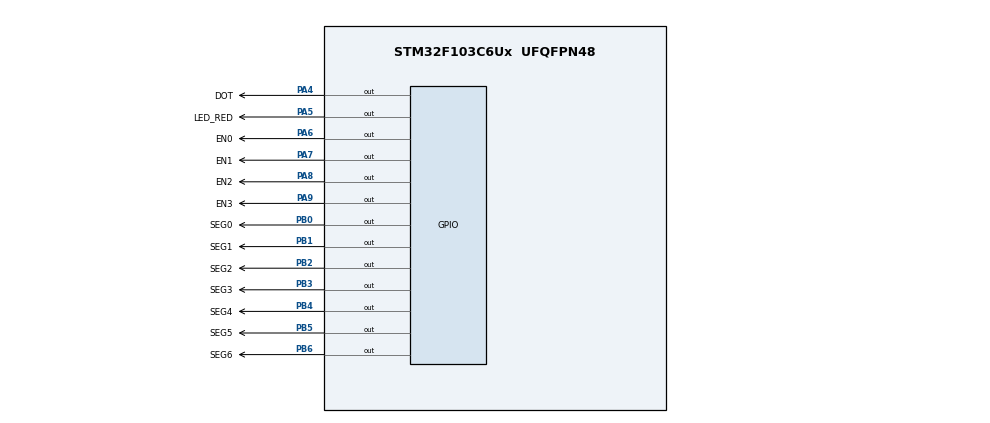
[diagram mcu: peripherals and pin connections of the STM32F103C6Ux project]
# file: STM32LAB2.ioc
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Mcu.Family=STM32F1
Mcu.Name=STM32F103C6Ux
Mcu.Package=UFQFPN48
NVIC.PriorityGroup=NVIC_PRIORITYGROUP_4
NVIC.TIM2_IRQn=true\:0\:0\:false\:false\:true\:true\:true
PA4.GPIO_Label=DOT
PA4.Signal=GPIO_Output
PA5.GPIO_Label=LED_RED
PA5.Signal=GPIO_Output
PA6.GPIO_Label=EN0
PA6.Signal=GPIO_Output
PA7.GPIO_Label=EN1
PA7.Signal=GPIO_Output
PA8.GPIO_Label=EN2
PA8.Signal=GPIO_Output
PA9.GPIO_Label=EN3
PA9.Signal=GPIO_Output
PB0.GPIO_Label=SEG0
PB0.Signal=GPIO_Output
PB1.GPIO_Label=SEG1
PB1.Signal=GPIO_Output
PB2.GPIO_Label=SEG2
PB2.Signal=GPIO_Output
PB3.GPIO_Label=SEG3
PB3.Signal=GPIO_Output
PB4.GPIO_Label=SEG4
PB4.Signal=GPIO_Output
PB5.GPIO_Label=SEG5
PB5.Signal=GPIO_Output
PB6.GPIO_Label=SEG6
PB6.Signal=GPIO_Output
ProjectManager.HeapSize=0x200
ProjectManager.StackSize=0x400
ProjectManager.TargetToolchain=STM32CubeIDE
RCC.APB1Freq_Value=8000000
RCC.APB2Freq_Value=8000000
TIM2.Period=9
TIM2.Prescaler=7999
VP_SYS_VS_ND.Mode=No_Debug
VP_TIM2_VS_ClockSourceINT.Mode=Internal
board=custom

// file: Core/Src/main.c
/* USER CODE BEGIN Header */
/**
  ******************************************************************************
  * @file           : main.c
  * @brief          : Main program body
  ******************************************************************************
  * @attention
  *
  * <h2><center>&copy; Copyright (c) 2024 STMicroelectronics.
  * All rights reserved.</center></h2>
  *
  * This software component is licensed by ST under BSD 3-Clause license,
  * the "License"; You may not use this file except in compliance with the
  * License. You may obtain a copy of the License at:
  *                        opensource.org/licenses/BSD-3-Clause
  *
  ******************************************************************************
  */
/* USER CODE END Header */
#include "main.h"

/* USER CODE BEGIN Includes */
#include "timer.h"
/* USER CODE END Includes */

TIM_HandleTypeDef htim2;

void SystemClock_Config(void);
static void MX_GPIO_Init(void);
static void MX_TIM2_Init(void);

/* USER CODE BEGIN 0 */
const int MAX_LED_MATRIX = 8;
int index_led_matrix = 0;
int index_led_matrix_shift = 0;
uint8_t matrix_buffer[8] = {0x00, 0xfc, 0xfe, 0x11, 0x11, 0xfe, 0xfc, 0x00}; // Display "A"

void displayLEDMatrix(int index)
{
	HAL_GPIO_WritePin(ROW0_GPIO_Port, ROW0_Pin, ((matrix_buffer[index] >> 0) & 1) ? GPIO_PIN_RESET : GPIO_PIN_SET);
	HAL_GPIO_WritePin(ROW1_GPIO_Port, ROW1_Pin, ((matrix_buffer[index] >> 1) & 1) ? GPIO_PIN_RESET : GPIO_PIN_SET);
	HAL_GPIO_WritePin(ROW2_GPIO_Port, ROW2_Pin, ((matrix_buffer[index] >> 2) & 1) ? GPIO_PIN_RESET : GPIO_PIN_SET);
	HAL_GPIO_WritePin(ROW3_GPIO_Port, ROW3_Pin, ((matrix_buffer[index] >> 3) & 1) ? GPIO_PIN_RESET : GPIO_PIN_SET);
	HAL_GPIO_WritePin(ROW4_GPIO_Port, ROW4_Pin, ((matrix_buffer[index] >> 4) & 1) ? GPIO_PIN_RESET : GPIO_PIN_SET);
	HAL_GPIO_WritePin(ROW5_GPIO_Port, ROW5_Pin, ((matrix_buffer[index] >> 5) & 1) ? GPIO_PIN_RESET : GPIO_PIN_SET);
	HAL_GPIO_WritePin(ROW6_GPIO_Port, ROW6_Pin, ((matrix_buffer[index] >> 6) & 1) ? GPIO_PIN_RESET : GPIO_PIN_SET);
	HAL_GPIO_WritePin(ROW7_GPIO_Port, ROW7_Pin, ((matrix_buffer[index] >> 7) & 1) ? GPIO_PIN_RESET : GPIO_PIN_SET);
}

void updateLEDMatrix(int index, int shift)
{
	int index_shift = (index + shift) % 8;

	switch(index)
	{
	case 0:
		HAL_GPIO_WritePin(ENM7_GPIO_Port, ENM7_Pin, 1);
		displayLEDMatrix(index_shift);
		HAL_GPIO_WritePin(ENM0_GPIO_Port, ENM0_Pin, 0);
		break;
	case 1:
		HAL_GPIO_WritePin(ENM0_GPIO_Port, ENM0_Pin, 1);
		displayLEDMatrix(index_shift);
		HAL_GPIO_WritePin(ENM1_GPIO_Port, ENM1_Pin, 0);
		break;
	case 2:
		HAL_GPIO_WritePin(ENM1_GPIO_Port, ENM1_Pin, 1);
		displayLEDMatrix(index_shift);
		HAL_GPIO_WritePin(ENM2_GPIO_Port, ENM2_Pin, 0);
		break;
	case 3:
		HAL_GPIO_WritePin(ENM2_GPIO_Port, ENM2_Pin, 1);
		displayLEDMatrix(index_shift);
		HAL_GPIO_WritePin(ENM3_GPIO_Port, ENM3_Pin, 0);
		break;
	case 4:
		HAL_GPIO_WritePin(ENM3_GPIO_Port, ENM3_Pin, 1);
		displayLEDMatrix(index_shift);
		HAL_GPIO_WritePin(ENM4_GPIO_Port, ENM4_Pin, 0);
		break;
	case 5:
		HAL_GPIO_WritePin(ENM4_GPIO_Port, ENM4_Pin, 1);
		displayLEDMatrix(index_shift);
		HAL_GPIO_WritePin(ENM5_GPIO_Port, ENM5_Pin, 0);
		break;
	case 6:
		HAL_GPIO_WritePin(ENM5_GPIO_Port, ENM5_Pin, 1);
		displayLEDMatrix(index_shift);
		HAL_GPIO_WritePin(ENM6_GPIO_Port, ENM6_Pin, 0);
		break;
	case 7:
		HAL_GPIO_WritePin(ENM6_GPIO_Port, ENM6_Pin, 1);
		displayLEDMatrix(index_shift);
		HAL_GPIO_WritePin(ENM7_GPIO_Port, ENM7_Pin, 0);
		break;
	default:
		break;
	}
}
/* USER CODE END 0 */

int main(void)
{

  /* MCU Configuration--------------------------------------------------------*/

  /* Reset of all peripherals, Initializes the Flash interface and the Systick. */
  HAL_Init();

  /* Configure the system clock */
  SystemClock_Config();

  /* Initialize all configured peripherals */
  MX_GPIO_Init();
  MX_TIM2_Init();
  /* USER CODE BEGIN 2 */
  HAL_TIM_Base_Start_IT(&htim2);
  /* USER CODE END 2 */

  /* Infinite loop */
  /* USER CODE BEGIN WHILE */
  HAL_GPIO_WritePin(GPIOA, EN0_Pin | EN1_Pin | EN2_Pin | EN3_Pin, 1);
  HAL_GPIO_WritePin(DOT_GPIO_Port, DOT_Pin, 1);
  HAL_GPIO_WritePin(GPIOA, ENM0_Pin | ENM1_Pin | ENM2_Pin | ENM3_Pin
		  | ENM4_Pin | ENM5_Pin | ENM6_Pin | ENM7_Pin, 1);

  set_timer(0, 250);
  while (1)
  {
	  if (timer_flag[0] == 1)
	  {
		  updateLEDMatrix(index_led_matrix, index_led_matrix_shift);
		  index_led_matrix++;
		  if (index_led_matrix >= MAX_LED_MATRIX)
		  {
			  index_led_matrix = 0;
			  index_led_matrix_shift++;
			  if (index_led_matrix_shift >= MAX_LED_MATRIX) index_led_matrix_shift = 0;
		  }
		  set_timer(0, 250);
	  }
    /* USER CODE END WHILE */

  }
}

void SystemClock_Config(void)
{
  RCC_OscInitTypeDef RCC_OscInitStruct = {0};
  RCC_ClkInitTypeDef RCC_ClkInitStruct = {0};

  /** Initializes the RCC Oscillators according to the specified parameters
  * in the RCC_OscInitTypeDef structure.
  */
  RCC_OscInitStruct.OscillatorType = RCC_OSCILLATORTYPE_HSI;
  RCC_OscInitStruct.HSIState = RCC_HSI_ON;
  RCC_OscInitStruct.HSICalibrationValue = RCC_HSICALIBRATION_DEFAULT;
  RCC_OscInitStruct.PLL.PLLState = RCC_PLL_NONE;
  if (HAL_RCC_OscConfig(&RCC_OscInitStruct) != HAL_OK)
  {
    Error_Handler();
  }
  /** Initializes the CPU, AHB and APB buses clocks
  */
  RCC_ClkInitStruct.ClockType = RCC_CLOCKTYPE_HCLK|RCC_CLOCKTYPE_SYSCLK
                              |RCC_CLOCKTYPE_PCLK1|RCC_CLOCKTYPE_PCLK2;
  RCC_ClkInitStruct.SYSCLKSource = RCC_SYSCLKSOURCE_HSI;
  RCC_ClkInitStruct.AHBCLKDivider = RCC_SYSCLK_DIV1;
  RCC_ClkInitStruct.APB1CLKDivider = RCC_HCLK_DIV1;
  RCC_ClkInitStruct.APB2CLKDivider = RCC_HCLK_DIV1;

  if (HAL_RCC_ClockConfig(&RCC_ClkInitStruct, FLASH_LATENCY_0) != HAL_OK)
  {
    Error_Handler();
  }
}

static void MX_TIM2_Init(void)
{

  TIM_ClockConfigTypeDef sClockSourceConfig = {0};
  TIM_MasterConfigTypeDef sMasterConfig = {0};

  htim2.Instance = TIM2;
  htim2.Init.Prescaler = 7999;
  htim2.Init.CounterMode = TIM_COUNTERMODE_UP;
  htim2.Init.Period = 9;
  htim2.Init.ClockDivision = TIM_CLOCKDIVISION_DIV1;
  htim2.Init.AutoReloadPreload = TIM_AUTORELOAD_PRELOAD_DISABLE;
  if (HAL_TIM_Base_Init(&htim2) != HAL_OK)
  {
    Error_Handler();
  }
  sClockSourceConfig.ClockSource = TIM_CLOCKSOURCE_INTERNAL;
  if (HAL_TIM_ConfigClockSource(&htim2, &sClockSourceConfig) != HAL_OK)
  {
    Error_Handler();
  }
  sMasterConfig.MasterOutputTrigger = TIM_TRGO_RESET;
  sMasterConfig.MasterSlaveMode = TIM_MASTERSLAVEMODE_DISABLE;
  if (HAL_TIMEx_MasterConfigSynchronization(&htim2, &sMasterConfig) != HAL_OK)
  {
    Error_Handler();
  }

}

static void MX_GPIO_Init(void)
{
  GPIO_InitTypeDef GPIO_InitStruct = {0};

  /* GPIO Ports Clock Enable */
  __HAL_RCC_GPIOA_CLK_ENABLE();
  __HAL_RCC_GPIOB_CLK_ENABLE();

  /*Configure GPIO pin Output Level */
  HAL_GPIO_WritePin(GPIOA, ENM0_Pin|ENM1_Pin|DOT_Pin|EN0_Pin
                          |EN1_Pin|EN2_Pin|EN3_Pin|ENM2_Pin
                          |ENM3_Pin|ENM4_Pin|ENM5_Pin|ENM6_Pin
                          |ENM7_Pin, GPIO_PIN_RESET);

  /*Configure GPIO pin Output Level */
  HAL_GPIO_WritePin(GPIOB, SEG0_Pin|SEG1_Pin|SEG2_Pin|ROW2_Pin
                          |ROW3_Pin|ROW4_Pin|ROW5_Pin|ROW6_Pin
                          |ROW7_Pin|SEG3_Pin|SEG4_Pin|SEG5_Pin
                          |SEG6_Pin|ROW0_Pin|ROW1_Pin, GPIO_PIN_RESET);

  /*Configure GPIO pins : ENM0_Pin ENM1_Pin DOT_Pin EN0_Pin
                           EN1_Pin EN2_Pin EN3_Pin ENM2_Pin
                           ENM3_Pin ENM4_Pin ENM5_Pin ENM6_Pin
                           ENM7_Pin */
  GPIO_InitStruct.Pin = ENM0_Pin|ENM1_Pin|DOT_Pin|EN0_Pin
                          |EN1_Pin|EN2_Pin|EN3_Pin|ENM2_Pin
                          |ENM3_Pin|ENM4_Pin|ENM5_Pin|ENM6_Pin
                          |ENM7_Pin;
  GPIO_InitStruct.Mode = GPIO_MODE_OUTPUT_PP;
  GPIO_InitStruct.Pull = GPIO_NOPULL;
  GPIO_InitStruct.Speed = GPIO_SPEED_FREQ_LOW;
  HAL_GPIO_Init(GPIOA, &GPIO_InitStruct);

  /*Configure GPIO pin : LED_RED_Pin */
  GPIO_InitStruct.Pin = LED_RED_Pin;
  GPIO_InitStruct.Mode = GPIO_MODE_INPUT;
  GPIO_InitStruct.Pull = GPIO_NOPULL;
  HAL_GPIO_Init(LED_RED_GPIO_Port, &GPIO_InitStruct);

  /*Configure GPIO pins : SEG0_Pin SEG1_Pin SEG2_Pin ROW2_Pin
                           ROW3_Pin ROW4_Pin ROW5_Pin ROW6_Pin
                           ROW7_Pin SEG3_Pin SEG4_Pin SEG5_Pin
                           SEG6_Pin ROW0_Pin ROW1_Pin */
  GPIO_InitStruct.Pin = SEG0_Pin|SEG1_Pin|SEG2_Pin|ROW2_Pin
                          |ROW3_Pin|ROW4_Pin|ROW5_Pin|ROW6_Pin
                          |ROW7_Pin|SEG3_Pin|SEG4_Pin|SEG5_Pin
                          |SEG6_Pin|ROW0_Pin|ROW1_Pin;
  GPIO_InitStruct.Mode = GPIO_MODE_OUTPUT_PP;
  GPIO_InitStruct.Pull = GPIO_NOPULL;
  GPIO_InitStruct.Speed = GPIO_SPEED_FREQ_LOW;
  HAL_GPIO_Init(GPIOB, &GPIO_InitStruct);

}

/* USER CODE BEGIN 4 */
void HAL_TIM_PeriodElapsedCallback ( TIM_HandleTypeDef * htim )
{
	timer_run();
}
/* USER CODE END 4 */

void Error_Handler(void)
{
  __disable_irq();
  while (1)
  {
  }
}

/************************ (C) COPYRIGHT STMicroelectronics *****END OF FILE****/
